VERSION 5.8 ;
BUSBITCHARS "[]" ;
DIVIDERCHAR "/" ;
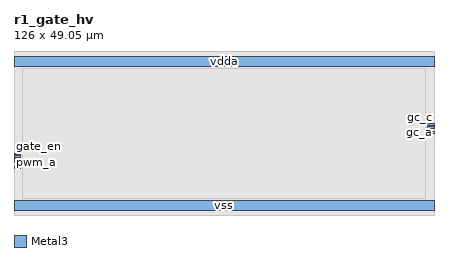
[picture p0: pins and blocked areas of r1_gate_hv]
MACRO r1_gate_hv
  CLASS BLOCK ;
  ORIGIN 0 0 ;
  FOREIGN r1_gate_hv 0 0 ;
  SIZE 126.000 BY 49.050 ;
  SYMMETRY X Y ;
  PIN pwm_a
    DIRECTION INOUT ;
    USE SIGNAL ;
    PORT
      LAYER Metal3 ;
        RECT 0.000 15.650 2.000 16.150 ;
    END
  END pwm_a
  PIN pwm_b
    DIRECTION INOUT ;
    USE SIGNAL ;
    PORT
      LAYER Metal3 ;
        RECT 0.000 16.450 2.000 16.950 ;
    END
  END pwm_b
  PIN pwm_c
    DIRECTION INOUT ;
    USE SIGNAL ;
    PORT
      LAYER Metal3 ;
        RECT 0.000 17.250 2.000 17.750 ;
    END
  END pwm_c
  PIN gate_en
    DIRECTION INOUT ;
    USE SIGNAL ;
    PORT
      LAYER Metal3 ;
        RECT 0.000 18.050 2.000 18.550 ;
    END
  END gate_en
  PIN gc_a
    DIRECTION INOUT ;
    USE SIGNAL ;
    PORT
      LAYER Metal3 ;
        RECT 124.000 24.450 126.000 24.950 ;
    END
  END gc_a
  PIN gc_b
    DIRECTION INOUT ;
    USE SIGNAL ;
    PORT
      LAYER Metal3 ;
        RECT 124.000 26.050 126.000 26.550 ;
    END
  END gc_b
  PIN gc_c
    DIRECTION INOUT ;
    USE SIGNAL ;
    PORT
      LAYER Metal3 ;
        RECT 124.000 26.850 126.000 27.350 ;
    END
  END gc_c
  PIN vss
    DIRECTION INOUT ;
    USE GROUND ;
    PORT
      LAYER Metal3 ;
        RECT 0.000 1.500 126.000 4.500 ;
    END
  END vss
  PIN vdda
    DIRECTION INOUT ;
    USE POWER ;
    PORT
      LAYER Metal3 ;
        RECT 0.000 44.550 126.000 47.550 ;
    END
  END vdda
  PIN vdd
    DIRECTION INOUT ;
    USE POWER ;
    PORT
      LAYER Metal3 ;
        RECT 0.000 14.080 2.000 14.580 ;
    END
  END vdd
  OBS
    LAYER Metal1 ;
      RECT 0.000 0.000 126.000 49.050 ;
    LAYER Metal2 ;
      RECT 0.000 0.000 126.000 49.050 ;
    LAYER Metal3 ;
      RECT 2.500 5.000 123.500 44.050 ;
  END
END r1_gate_hv
END LIBRARY
